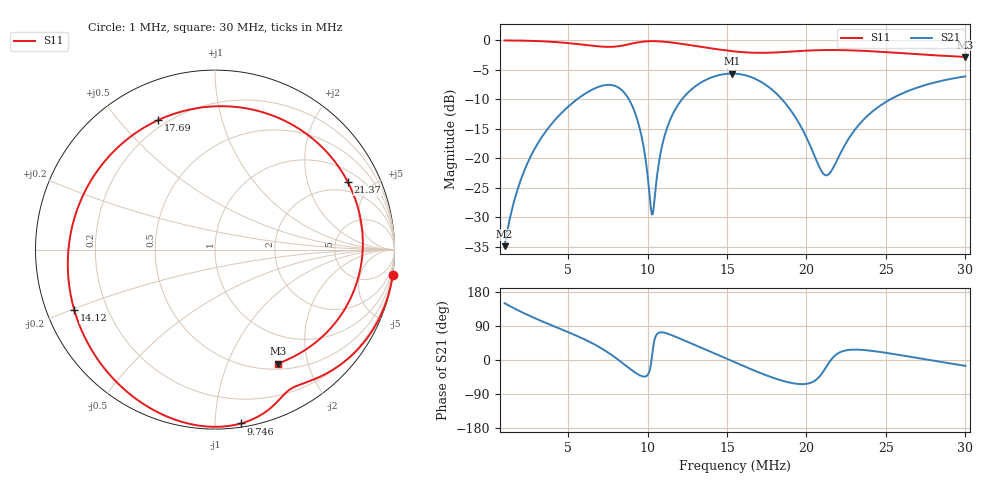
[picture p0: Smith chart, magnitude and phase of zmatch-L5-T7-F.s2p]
# HZ S RI R 50
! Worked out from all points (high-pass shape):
!   505 points, 1 MHz to 30 MHz, reference 50 ohm
!   highest |S21| = -5.62 dB at 15.33 MHz (marker M1); lowest = -34.9 dB at 1 MHz (marker M2)
!   |S21| within 3 dB of the highest: 12.63 MHz to 17.95 MHz (5.317 MHz wide, 34.8 % of centre); 26.35 MHz to end of sweep (the widest 2 of 3)
!   lowest |S11| = -2.8 dB at 30 MHz (marker M3), VSWR 6.28, Z = 28.7 - j76.9 ohm
!   |S11| at or under -10 dB: nowhere
!   S12 and S22 are empty: the file has one direction only
!   S11 on the Smith chart (normalised r, x): 1 MHz: -0, -14; 9.746 MHz: 0.02, -1.16; 14.12 MHz: 0.08, -0.20; 17.69 MHz: 0.17, +0.64; 21.37 MHz: 1.49, +3.60; 30 MHz: 0.57, -1.54
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1000000  0.9905 -0.1421  -0.0155 0.00907  0 0  0 0
1805560  0.9656 -0.255  -0.0361 0.0402  0 0  0 0
2783740  0.9127 -0.3884  -0.0435 0.1046  0 0  0 0
5833360  0.6088 -0.6966  0.1772 0.2866  0 0  0 0
7041700  0.4768 -0.7506  0.3477 0.2175  0 0  0 0
8307580  0.3748 -0.8178  0.3849 -0.0298  0 0  0 0
9113140  0.2793 -0.9062  0.2273 -0.1318  0 0  0 0
9746080  0.146 -0.9683  0.0909 -0.0868  0 0  0 0
1.026394e7  0.012 -0.9873  0.0333 0.00322  0 0  0 0
1.066672e7  -0.0969 -0.9796  0.0271 0.0793  0 0  0 0
1.112704e7  -0.2194 -0.9486  0.0532 0.1563  0 0  0 0
1.181752e7  -0.391 -0.8652  0.1341 0.2357  0 0  0 0
1.411912e7  -0.7843 -0.3353  0.4642 0.1613  0 0  0 0
1.532746e7  -0.8096 0.0574  0.5232 -0.0263  0 0  0 0
1.550008e7  -0.7987 0.116  0.5201 -0.0552  0 0  0 0
1.76866e7  -0.317 0.7212  0.2861 -0.2748  0 0  0 0
1.895248e7  0.1387 0.7923  0.1319 -0.2262  0 0  0 0
2.033344e7  0.5561 0.6077  0.0614 -0.1022  0 0  0 0
2.136916e7  0.7404 0.3756  0.0718 -0.0123  0 0  0 0
2.321044e7  0.8205 -0.0335  0.1658 0.0856  0 0  0 0
2.51668e7  0.7185 -0.3393  0.2956 0.0951  0 0  0 0
3.000016e7  0.35 -0.635  0.4782 -0.1327  0 0  0 0
